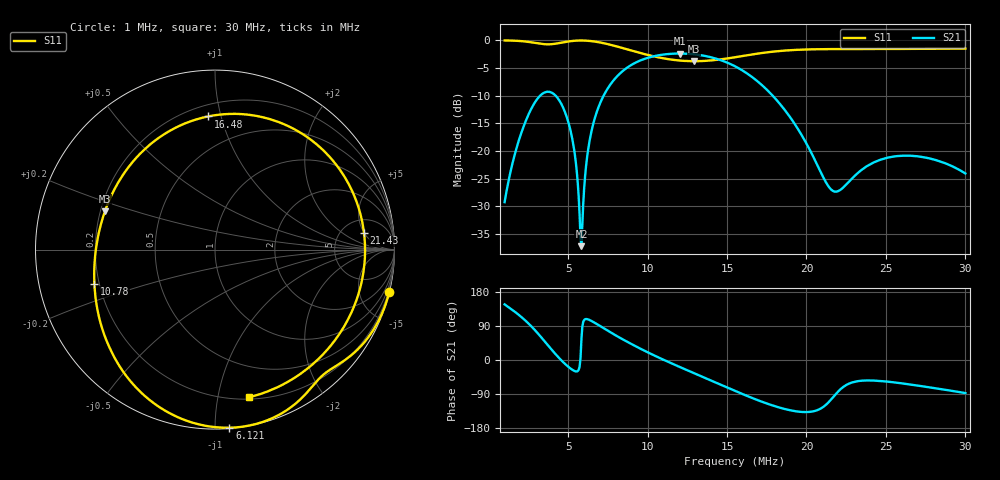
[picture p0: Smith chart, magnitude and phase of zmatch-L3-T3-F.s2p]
# HZ S RI R 50
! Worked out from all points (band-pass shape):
!   505 points, 1 MHz to 30 MHz, reference 50 ohm
!   highest |S21| = -2.36 dB at 12.05 MHz (marker M1); lowest = -37.2 dB at 5.833 MHz (marker M2)
!   |S21| within 3 dB of the highest: 8.507 MHz to 15.93 MHz (7.425 MHz wide, 60.8 % of centre)
!   lowest |S11| = -3.8 dB at 12.91 MHz (marker M3), VSWR 4.70, Z = 10.9 + j8.02 ohm
!   |S11| at or under -10 dB: nowhere
!   S12 and S22 are empty: the file has one direction only
!   S11 on the Smith chart (normalised r, x): 1 MHz: 0.01, -8.34; 6.121 MHz: 0.00, -1.08; 10.78 MHz: 0.18, -0.13; 16.48 MHz: 0.27, +0.91; 21.43 MHz: 8.11, +4.94; 30 MHz: 0.21, -1.23
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1000000  0.9714 -0.2364  -0.0289 0.0189  0 0  0 0
2438500  0.8046 -0.5466  -0.0316 0.2013  0 0  0 0
3186520  0.676 -0.6471  0.128 0.284  0 0  0 0
3877000  0.584 -0.7154  0.2915 0.1777  0 0  0 0
5142880  0.3729 -0.9114  0.1429 -0.0587  0 0  0 0
5488120  0.2784 -0.9557  0.0672 -0.039  0 0  0 0
5833360  0.1727 -0.9836  0.00826 0.0111  0 0  0 0
6121060  0.0802 -0.9925  -0.0225 0.0685  0 0  0 0
6638920  -0.0858 -0.9747  -0.0298 0.1875  0 0  0 0
7502020  -0.3268 -0.8661  0.083 0.3611  0 0  0 0
8940520  -0.5715 -0.5793  0.4358 0.4074  0 0  0 0
1.066672e7  -0.6707 -0.2138  0.7277 0.0902  0 0  0 0
1.07818e7  -0.672 -0.1909  0.7354 0.0621  0 0  0 0
1.204768e7  -0.6557 0.0522  0.7208 -0.2468  0 0  0 0
1.291078e7  -0.6134 0.2125  0.6175 -0.426  0 0  0 0
1.550008e7  -0.2708 0.6506  0.0864 -0.5777  0 0  0 0
1.647826e7  -0.0388 0.7419  -0.0711 -0.4731  0 0  0 0
1.814692e7  0.3985 0.6924  -0.1587 -0.2384  0 0  0 0
2.033344e7  0.7693 0.3152  -0.0682 -0.0655  0 0  0 0
2.14267e7  0.8303 0.092  -0.016 -0.0443  0 0  0 0
2.51668e7  0.672 -0.5001  0.0471 -0.0738  0 0  0 0
3.000016e7  0.1868 -0.8231  0.00295 -0.0627  0 0  0 0
